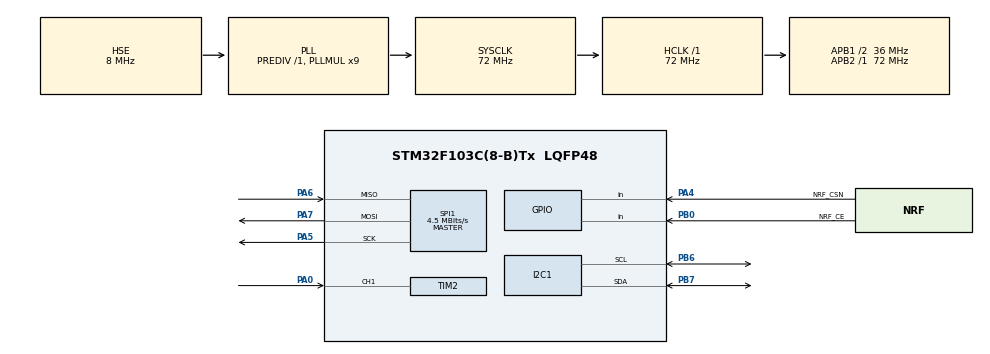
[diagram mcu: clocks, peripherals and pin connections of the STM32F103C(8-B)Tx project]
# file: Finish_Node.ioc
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Mcu.Family=STM32F1
Mcu.Name=STM32F103C(8-B)Tx
Mcu.Package=LQFP48
NVIC.PriorityGroup=NVIC_PRIORITYGROUP_4
NVIC.TIM2_IRQn=true\:0\:0\:false\:false\:true\:true\:true\:true
PA0-WKUP.Signal=S_TIM2_CH1_ETR
PA13.Mode=Serial_Wire
PA13.Signal=SYS_JTMS-SWDIO
PA14.Mode=Serial_Wire
PA14.Signal=SYS_JTCK-SWCLK
PA4.GPIO_Label=NRF_CSN
PA4.Signal=GPIO_Input
PA5.Mode=Full_Duplex_Master
PA5.Signal=SPI1_SCK
PA6.Mode=Full_Duplex_Master
PA6.Signal=SPI1_MISO
PA7.Mode=Full_Duplex_Master
PA7.Signal=SPI1_MOSI
PB0.GPIO_Label=NRF_CE
PB0.Signal=GPIO_Input
PB6.Mode=I2C
PB6.Signal=I2C1_SCL
PB7.Mode=I2C
PB7.Signal=I2C1_SDA
PD0-OSC_IN.Mode=HSE-External-Oscillator
PD0-OSC_IN.Signal=RCC_OSC_IN
PD1-OSC_OUT.Mode=HSE-External-Oscillator
PD1-OSC_OUT.Signal=RCC_OSC_OUT
ProjectManager.HeapSize=0x200
ProjectManager.StackSize=0x400
ProjectManager.TargetToolchain=MDK-ARM V5.32
RCC.AHBFreq_Value=72000000
RCC.APB1CLKDivider=RCC_HCLK_DIV2
RCC.APB1Freq_Value=36000000
RCC.APB1TimFreq_Value=72000000
RCC.APB2Freq_Value=72000000
RCC.APB2TimFreq_Value=72000000
RCC.HCLKFreq_Value=72000000
RCC.PLLMUL=RCC_PLL_MUL9
RCC.PLLSourceVirtual=RCC_PLLSOURCE_HSE
RCC.SYSCLKFreq_VALUE=72000000
RCC.SYSCLKSource=RCC_SYSCLKSOURCE_PLLCLK
RCC.USBFreq_Value=72000000
SH.S_TIM2_CH1_ETR.0=TIM2_CH1,Input_Capture1_from_TI1
SPI1.BaudRatePrescaler=SPI_BAUDRATEPRESCALER_16
SPI1.CalculateBaudRate=4.5 MBits/s
SPI1.Direction=SPI_DIRECTION_2LINES
SPI1.Mode=SPI_MODE_MASTER
SPI1.VirtualType=VM_MASTER
TIM2.Channel-Input_Capture1_from_TI1=TIM_CHANNEL_1
TIM2.ICFilter_CH1=8
TIM2.ICPolarity_CH1=TIM_INPUTCHANNELPOLARITY_FALLING
TIM2.Prescaler=71
board=custom

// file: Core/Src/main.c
/* USER CODE BEGIN Header */
/**
  ******************************************************************************
  * @file           : main.c
  * @brief          : Main program body (Finish Node)
  ******************************************************************************
  */
/* USER CODE END Header */
#include "main.h"
#include "i2c.h"
#include "spi.h"
#include "tim.h"
#include "gpio.h"

/* USER CODE BEGIN Includes */
#include <stdio.h>
#include "nrf24l01p.h"
#include "oled.h"
/* USER CODE END Includes */

/* USER CODE BEGIN PV */
// --- ?????? ---
uint8_t RxData[32];         // ???????
uint8_t race_state = 0;     // ???: 0=????, 1=????, 2=????
uint32_t finish_cnt = 0;    // ??????????
uint16_t overflow_cnt = 0;  // ???????
float final_time = 0.0f;    // ????
char disp_buff[20];         // ???????
/* USER CODE END PV */

void SystemClock_Config(void);
static void MX_GPIO_Init(void); // ??????????????

/* USER CODE BEGIN 0 */

// 1. ??????? (? 65.536ms ????)
void HAL_TIM_PeriodElapsedCallback(TIM_HandleTypeDef *htim)
{
    if (htim->Instance == TIM2) {
        overflow_cnt++;
    }
}

// 2. ?????? (????? - ?????)
void HAL_TIM_IC_CaptureCallback(TIM_HandleTypeDef *htim)
{
    // ???“????”???,????1??
    if (htim->Channel == HAL_TIM_ACTIVE_CHANNEL_1 && race_state == 1)
    {
        // A. ???????
        finish_cnt = HAL_TIM_ReadCapturedValue(htim, TIM_CHANNEL_1);

        // B. ?????
        HAL_TIM_Base_Stop_IT(&htim2);
        HAL_TIM_IC_Stop_IT(&htim2, TIM_CHANNEL_1);

        // C. ???? (??: ?)
        uint64_t total_us = ((uint64_t)overflow_cnt * 65536) + finish_cnt;
        final_time = (float)total_us / 1000000.0f;

        // D. ????
        race_state = 2;
    }
}
/* USER CODE END 0 */

int main(void)
{

  /* MCU Configuration--------------------------------------------------------*/

  /* Reset of all peripherals, Initializes the Flash interface and the Systick. */
  HAL_Init();

  /* Configure the system clock */
  SystemClock_Config();

  /* Initialize all configured peripherals */

  // 1. ??? GPIO (??:?????? PB8/PB9 ???)
  MX_GPIO_Init();

  // 2. ???????
  MX_I2C1_Init(); // ?????I2C,????????
  MX_SPI1_Init();
  MX_TIM2_Init();

  /* USER CODE BEGIN 2 */

  // --- ???? ---

  // 1. ??? OLED (PB8/PB9)
  OLED_Init();
  OLED_Clear();
  OLED_ShowString(0, 0, (uint8_t*)"System Init...", 16);

  // 2. ??? NRF (??40)
  nrf24l01p_rx_init(40, _250kbps);

  HAL_Delay(500);
  OLED_Clear();
  OLED_ShowString(0, 0, (uint8_t*)"Wait for GO...", 16);

  /* USER CODE END 2 */

  /* Infinite loop */
  while (1)
  {

    /* USER CODE BEGIN 3 */

      // --- ??0: ???? ---
      if (race_state == 0)
      {
          // ??????
          if(nrf24l01p_rx_receive(RxData) == 1)
          {
              race_state = 1; // ????

              // ?????
              overflow_cnt = 0;
              __HAL_TIM_SET_COUNTER(&htim2, 0);

              // ???????
              HAL_TIM_Base_Start_IT(&htim2);
              HAL_TIM_IC_Start_IT(&htim2, TIM_CHANNEL_1);

              // ????
              OLED_Clear();
              OLED_ShowString(0, 0, (uint8_t*)"RUNNING!!!", 16);
          }
      }

      // --- ??1: ???? ---
      // (?????,????????)

      // --- ??2: ???? ---
      else if (race_state == 2)
      {
          OLED_ShowString(0, 0, (uint8_t*)"FINISH!     ", 16);

          // ????????
          sprintf(disp_buff, "Time: %.3fs", final_time);

          // ???? (???? OLED ?????)
          OLED_ShowString(0, 2, (uint8_t*)disp_buff, 16);

          // ????????
          HAL_Delay(200);

          // ??????????,??????????
      }
  }
  /* USER CODE END 3 */
}

void SystemClock_Config(void)
{
  RCC_OscInitTypeDef RCC_OscInitStruct = {0};
  RCC_ClkInitTypeDef RCC_ClkInitStruct = {0};

  RCC_OscInitStruct.OscillatorType = RCC_OSCILLATORTYPE_HSE;
  RCC_OscInitStruct.HSEState = RCC_HSE_ON;
  RCC_OscInitStruct.HSEPredivValue = RCC_HSE_PREDIV_DIV1;
  RCC_OscInitStruct.HSIState = RCC_HSI_ON;
  RCC_OscInitStruct.PLL.PLLState = RCC_PLL_ON;
  RCC_OscInitStruct.PLL.PLLSource = RCC_PLLSOURCE_HSE;
  RCC_OscInitStruct.PLL.PLLMUL = RCC_PLL_MUL9;
  if (HAL_RCC_OscConfig(&RCC_OscInitStruct) != HAL_OK)
  {
    Error_Handler();
  }

  RCC_ClkInitStruct.ClockType = RCC_CLOCKTYPE_HCLK|RCC_CLOCKTYPE_SYSCLK
                              |RCC_CLOCKTYPE_PCLK1|RCC_CLOCKTYPE_PCLK2;
  RCC_ClkInitStruct.SYSCLKSource = RCC_SYSCLKSOURCE_PLLCLK;
  RCC_ClkInitStruct.AHBCLKDivider = RCC_SYSCLK_DIV1;
  RCC_ClkInitStruct.APB1CLKDivider = RCC_HCLK_DIV2;
  RCC_ClkInitStruct.APB2CLKDivider = RCC_HCLK_DIV1;

  if (HAL_RCC_ClockConfig(&RCC_ClkInitStruct, FLASH_LATENCY_2) != HAL_OK)
  {
    Error_Handler();
  }
}

static void MX_GPIO_Init(void)
{
  GPIO_InitTypeDef GPIO_InitStruct = {0};

  /* GPIO Ports Clock Enable */
  __HAL_RCC_GPIOD_CLK_ENABLE();
  __HAL_RCC_GPIOA_CLK_ENABLE();
  __HAL_RCC_GPIOB_CLK_ENABLE(); // ?? B ???

  /*Configure GPIO pin Output Level */
  // ???? PB8 ? PB9 (I2C ????)
  HAL_GPIO_WritePin(GPIOB, GPIO_PIN_8|GPIO_PIN_9, GPIO_PIN_SET);

  /*Configure GPIO pins : PB8 PB9 */
  GPIO_InitStruct.Pin = GPIO_PIN_8|GPIO_PIN_9;

  // ????:???? (Open Drain),????OLED??
  GPIO_InitStruct.Mode = GPIO_MODE_OUTPUT_OD;

  GPIO_InitStruct.Pull = GPIO_PULLUP; // ??
  GPIO_InitStruct.Speed = GPIO_SPEED_FREQ_HIGH; // ??
  HAL_GPIO_Init(GPIOB, &GPIO_InitStruct);
}

void Error_Handler(void)
{
  __disable_irq();
  while (1)
  {
  }
}
